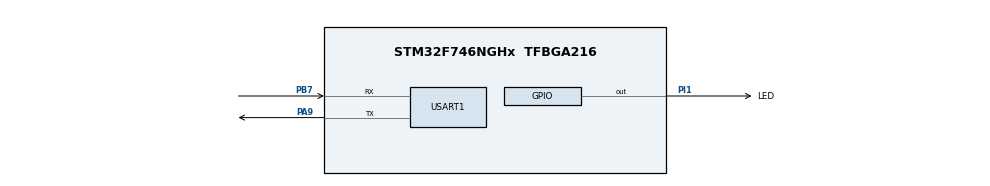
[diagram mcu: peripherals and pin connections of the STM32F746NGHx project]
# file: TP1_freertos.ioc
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FREERTOS.Tasks01=defaultTask,0,128,StartDefaultTask,Default,NULL,Dynamic,NULL,NULL
Mcu.Family=STM32F7
Mcu.Name=STM32F746NGHx
Mcu.Package=TFBGA216
NVIC.PriorityGroup=NVIC_PRIORITYGROUP_4
NVIC.TIM6_DAC_IRQn=true\:15\:0\:false\:false\:true\:false\:false\:true\:true
NVIC.TimeBase=TIM6_DAC_IRQn
NVIC.TimeBaseIP=TIM6
PA13.Mode=Serial_Wire
PA13.Signal=SYS_JTMS-SWDIO
PA14.Mode=Serial_Wire
PA14.Signal=SYS_JTCK-SWCLK
PA9.Mode=Asynchronous
PA9.Signal=USART1_TX
PB7.Mode=Asynchronous
PB7.Signal=USART1_RX
PH0/OSC_IN.Mode=HSE-External-Oscillator
PH0/OSC_IN.Signal=RCC_OSC_IN
PH1/OSC_OUT.Mode=HSE-External-Oscillator
PH1/OSC_OUT.Signal=RCC_OSC_OUT
PI1.GPIO_Label=LED
PI1.Signal=GPIO_Output
ProjectManager.HeapSize=0x200
ProjectManager.StackSize=0x400
ProjectManager.TargetToolchain=STM32CubeIDE
RCC.AHBFreq_Value=216000000
RCC.APB1CLKDivider=RCC_HCLK_DIV4
RCC.APB1Freq_Value=54000000
RCC.APB1TimFreq_Value=108000000
RCC.APB2CLKDivider=RCC_HCLK_DIV2
RCC.APB2Freq_Value=108000000
RCC.APB2TimFreq_Value=216000000
RCC.CortexFreq_Value=216000000
RCC.HCLKFreq_Value=216000000
RCC.HSE_VALUE=25000000
RCC.HSI_VALUE=16000000
RCC.LSE_VALUE=32768
RCC.PLLM=25
RCC.PLLN=432
RCC.PLLSourceVirtual=RCC_PLLSOURCE_HSE
RCC.SYSCLKFreq_VALUE=216000000
RCC.SYSCLKSource=RCC_SYSCLKSOURCE_PLLCLK
RCC.USBFreq_Value=216000000
RCC.VCOOutputFreq_Value=432000000
USART1.VirtualMode-Asynchronous=VM_ASYNC
VP_FREERTOS_VS_CMSIS_V1.Mode=CMSIS_V1
VP_SYS_VS_tim6.Mode=TIM6
board=STM32F746G-DISCO

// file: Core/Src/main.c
/* USER CODE BEGIN Header */
/**
 ******************************************************************************
 * @file           : main.c
 * @brief          : Main program body
 ******************************************************************************
 * @attention
 *
 * Copyright (c) 2024 STMicroelectronics.
 * All rights reserved.
 *
 * This software is licensed under terms that can be found in the LICENSE file
 * in the root directory of this software component.
 * If no LICENSE file comes with this software, it is provided AS-IS.
 *
 ******************************************************************************
 */
/* USER CODE END Header */
#include "main.h"
#include "cmsis_os.h"
#include "usart.h"
#include "gpio.h"

/* USER CODE BEGIN Includes */
#include <stdio.h>
#include "task.h"
#include "semphr.h"
#include "stm32F7xx.h"
/* USER CODE END Includes */

/* USER CODE BEGIN PV */
#define MS_T0_TICKS(ms) ((TickType_t)(ms * configTICK_RATE_HZ / 1000))
/* USER CODE END PV */

void SystemClock_Config(void);
void MX_FREERTOS_Init(void);

/* USER CODE BEGIN 0 */

TaskHandle_t handle_blink_led;
TaskHandle_t handle_uart;
TaskHandle_t pdTASK_GIVE_HANDLE = NULL;
TaskHandle_t pdTASK_TAKE_HANDLE = NULL;

int __io_putchar(int chr)
{
	HAL_UART_Transmit(&huart1, (uint8_t *)&chr, 1, HAL_MAX_DELAY);
	return chr;
}

void HAL_UART_RxCpltCallback(UART_HandleTypeDef *huart)
{
	if (huart->Instance == USART1) // On s'assure les interruptions
	{
		BaseType_t xHigherPriorityTaskWoken; //Pour l'instant on admet
		// Sans poser de questions SVP

		//uart_rx_flag = 1;
		vTaskNotifyGiveFromISR(handle_uart, &xHigherPriorityTaskWoken);

		portYIELD_FROM_ISR(xHigherPriorityTaskWoken);
	}
}

void task_blink_led(void * unused)
{
	for(;;)
	{
		HAL_GPIO_TogglePin(LED_GPIO_Port, LED_Pin);
		printf ("\r\n LED \r\n");
		vTaskDelay(100/portTICK_PERIOD_MS);
	}
}

void task_uart(void * unused)
{
	for(;;)
	{
		char chr;
		HAL_UART_Receive_IT(&huart1, (uint8_t *)&chr, 1); //IT pour d'accord avec interruptions
		ulTaskNotifyTake(pdTRUE, portMAX_DELAY);
		HAL_UART_Transmit(&huart1, (uint8_t *)&chr, 1, HAL_MAX_DELAY);
	}
}

//Sémaphores de taskGive et taskTake
SemaphoreHandle_t xSemaphore = NULL;

void taskGive(void *pvParameters){
	TickType_t xDelay = 100/ portTICK_PERIOD_MS;

	for(;;){
//		printf("\r\n taskGive : Prêt à donner le sémaphore \r\n");
//		xSemaphoreGive(xSemaphore);

		printf("\r\n taskGive : Prêt à enovyer la notification \r\n");
		xTaskNotifyGive(pdTASK_TAKE_HANDLE);//Envoie une notification à taskTake

		printf("\r\n taskGive : Notification envoyée \r\n");
//		printf("\r\n taskGive : Sémaphore deonné \r\n");

		vTaskDelay(xDelay);

		xDelay += 100/portTICK_PERIOD_MS; //Augmente le delai de 100ms
	}
}

void taskTake(void *pvParameters){
	for(;;){
//		printf("\r\n taskTake : Prêt à prendre le sémaphore \r\n");
		printf("\r\n taskTake : Prêt à recevoir la notification \r\n");

		//Attend la notification
		uint32_t ulNotificationValue = ulTaskNotifyTake(pdTRUE, MS_T0_TICKS(1000));

		if (ulNotificationValue >0){
			printf("\r\n taskTake: Notification reçue \r\n");
		}
//		if (xSemaphoreTake(xSemaphore, MS_T0_TICKS(1000)) == pdTRUE){
//			printf("\r\n taskTake: Sémaphore pris \r\n");
//		}
		else{
			printf("\r\n taskTake: Timeout de la notification, déclenchement d'un reset\r\n");
//			printf("\r\n taskTake: échec de la prise du sémaphore, déclenchement d'un reset \r\n");
			NVIC_SystemReset();//Reset logiciel du microcontrôleur
		}
	}
}

/* USER CODE END 0 */

int main(void)
{

	/* MCU Configuration--------------------------------------------------------*/

	/* Reset of all peripherals, Initializes the Flash interface and the Systick. */
	HAL_Init();

	/* Configure the system clock */
	SystemClock_Config();

	/* Initialize all configured peripherals */
	MX_GPIO_Init();
	MX_USART1_UART_Init();
	/* USER CODE BEGIN 2 */

/*	xSemaphore = xSemaphoreCreateBinary();

	if (xSemaphore != NULL){
		xTaskCreate(taskGive, "TaskGive", configMINIMAL_STACK_SIZE, NULL,4,NULL);
		xTaskCreate(taskTake, "TaskTake", configMINIMAL_STACK_SIZE, NULL,3,NULL);
		vTaskStartScheduler();
	}*/

	xTaskCreate(taskGive, "TaskGive", configMINIMAL_STACK_SIZE, NULL,4, &pdTASK_GIVE_HANDLE);
	xTaskCreate(taskTake, "TaskTake", configMINIMAL_STACK_SIZE, NULL,3, &pdTASK_TAKE_HANDLE);

/*	BaseType_t ret;

	ret = xTaskCreate(
			task_blink_led, //premiere interruption dans le flash
			"Blink LED", //un nom de la fonction
			256,//taille de la pile (en mot de 32 bits). si on met 1000000, il y a un "Error creating task blink led"
			NULL,//Paramètre  (pas utilisé ici)
			1,//(priorité)
			&handle_blink_led
	);

	if (ret != pdPASS)
	{
		printf("Error creating task blink led\r\n");
		Error_Handler();

	}

	ret = xTaskCreate (
			task_uart,
			"UART",
			256,
			NULL,
			2,
			&handle_uart
	);

	if (ret != pdPASS)
	{
		printf("Error creating task uart\r\n");
		Error_Handler();

	}

	printf("Task creation successful\r\n");

	vTaskStartScheduler();*/// Boucle infinie, on exécute rien après !!!

	/* USER CODE END 2 */

	/* Call init function for freertos objects (in freertos.c) */
	MX_FREERTOS_Init();

	/* Start scheduler */
	osKernelStart();

	/* We should never get here as control is now taken by the scheduler */
	/* Infinite loop */
	/* USER CODE BEGIN WHILE */
	while (1)
	{
		/*Faire clignoter la LED*/

		//		HAL_GPIO_TogglePin(GPIOI, LED_Pin, GPIO_PIN_SET);

		//		HAL_Delay(100);

		//		HAL_GPIO_WritePin(GPIOI, LED_Pin, GPIO_PIN_RESET);

		//		HAL_Delay(100);

		char chr;
		HAL_UART_Receive(&huart1, (uint8_t *)&chr, 1, HAL_MAX_DELAY);

		//		HAL_GPIO_TogglePin(GPIOI, LED_Pin);//quand il y a un chr, le led s'allume

		HAL_UART_Transmit(&huart1, (uint8_t *)&chr, 1, HAL_MAX_DELAY);

		/* USER CODE END WHILE */

	}
}

void SystemClock_Config(void)
{
	RCC_OscInitTypeDef RCC_OscInitStruct = {0};
	RCC_ClkInitTypeDef RCC_ClkInitStruct = {0};

	/** Configure the main internal regulator output voltage
	 */
	__HAL_RCC_PWR_CLK_ENABLE();
	__HAL_PWR_VOLTAGESCALING_CONFIG(PWR_REGULATOR_VOLTAGE_SCALE2);

	/** Initializes the RCC Oscillators according to the specified parameters
	 * in the RCC_OscInitTypeDef structure.
	 */
	RCC_OscInitStruct.OscillatorType = RCC_OSCILLATORTYPE_HSI;
	RCC_OscInitStruct.HSIState = RCC_HSI_ON;
	RCC_OscInitStruct.HSICalibrationValue = RCC_HSICALIBRATION_DEFAULT;
	RCC_OscInitStruct.PLL.PLLState = RCC_PLL_ON;
	RCC_OscInitStruct.PLL.PLLSource = RCC_PLLSOURCE_HSI;
	RCC_OscInitStruct.PLL.PLLM = 10;
	RCC_OscInitStruct.PLL.PLLN = 210;
	RCC_OscInitStruct.PLL.PLLP = RCC_PLLP_DIV2;
	RCC_OscInitStruct.PLL.PLLQ = 2;
	if (HAL_RCC_OscConfig(&RCC_OscInitStruct) != HAL_OK)
	{
		Error_Handler();
	}

	/** Initializes the CPU, AHB and APB buses clocks
	 */
	RCC_ClkInitStruct.ClockType = RCC_CLOCKTYPE_HCLK|RCC_CLOCKTYPE_SYSCLK
			|RCC_CLOCKTYPE_PCLK1|RCC_CLOCKTYPE_PCLK2;
	RCC_ClkInitStruct.SYSCLKSource = RCC_SYSCLKSOURCE_PLLCLK;
	RCC_ClkInitStruct.AHBCLKDivider = RCC_SYSCLK_DIV1;
	RCC_ClkInitStruct.APB1CLKDivider = RCC_HCLK_DIV4;
	RCC_ClkInitStruct.APB2CLKDivider = RCC_HCLK_DIV2;

	if (HAL_RCC_ClockConfig(&RCC_ClkInitStruct, FLASH_LATENCY_5) != HAL_OK)
	{
		Error_Handler();
	}
}

void HAL_TIM_PeriodElapsedCallback(TIM_HandleTypeDef *htim)
{
	if (htim->Instance == TIM6) {
		HAL_IncTick();
	}
}

void Error_Handler(void)
{
	__disable_irq();
	while (1)
	{
	}
}
